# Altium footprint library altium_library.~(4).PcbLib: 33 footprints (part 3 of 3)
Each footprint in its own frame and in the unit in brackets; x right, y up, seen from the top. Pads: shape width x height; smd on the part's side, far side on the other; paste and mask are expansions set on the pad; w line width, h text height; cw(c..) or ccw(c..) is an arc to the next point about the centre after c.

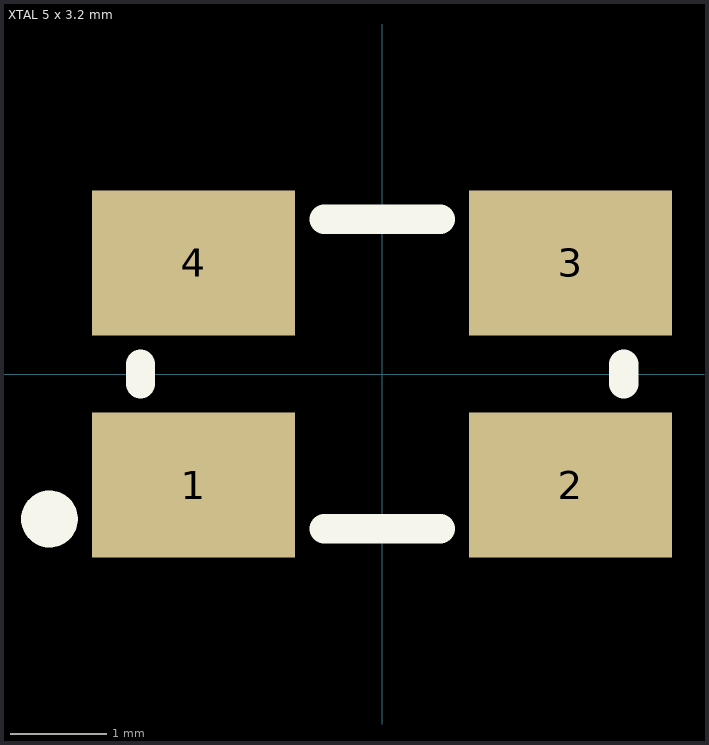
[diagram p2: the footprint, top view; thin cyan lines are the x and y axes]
## XTAL 5 x 3.2 mm [mm]
pads (4):
  rect 2.1x1.5 smd: 1(-1.95,-1.15) 2(1.95,-1.15) 3(1.95,1.15) 4(-1.95,1.15)
Top Overlay:
  circle w0.305: c-3.441,-1.5 r0.141
  lines w0.305: -2.5,-0.1 -2.5,0.1 ; -0.6,-1.6 0.6,-1.6 ; -0.6,1.6 0.6,1.6 ; 2.5,-0.1 2.5,0.1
